VERSION 5.7 ;
  NOWIREEXTENSIONATPIN ON ;
  DIVIDERCHAR "/" ;
  BUSBITCHARS "[]" ;
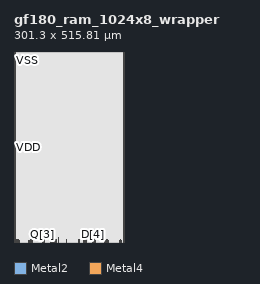
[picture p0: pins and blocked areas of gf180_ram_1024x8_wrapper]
MACRO gf180_ram_1024x8_wrapper
  CLASS BLOCK ;
  FOREIGN gf180_ram_1024x8_wrapper ;
  ORIGIN 0.000 0.000 ;
  SIZE 301.300 BY 515.810 ;
  PIN A[0]
    DIRECTION INPUT ;
    USE SIGNAL ;
    ANTENNADIFFAREA 0.928400 ;
    PORT
      LAYER Metal2 ;
        RECT 119.850 0.000 120.630 12.275 ;
    END
  END A[0]
  PIN A[1]
    DIRECTION INPUT ;
    USE SIGNAL ;
    ANTENNADIFFAREA 0.928400 ;
    PORT
      LAYER Metal2 ;
        RECT 113.930 0.000 114.720 6.000 ;
    END
  END A[1]
  PIN A[2]
    DIRECTION INPUT ;
    USE SIGNAL ;
    ANTENNADIFFAREA 0.928400 ;
    PORT
      LAYER Metal2 ;
        RECT 108.005 0.000 108.795 6.000 ;
    END
  END A[2]
  PIN A[3]
    DIRECTION INPUT ;
    USE SIGNAL ;
    ANTENNADIFFAREA 0.928400 ;
    PORT
      LAYER Metal2 ;
        RECT 196.925 0.000 197.715 6.000 ;
    END
  END A[3]
  PIN A[4]
    DIRECTION INPUT ;
    USE SIGNAL ;
    ANTENNADIFFAREA 0.928400 ;
    PORT
      LAYER Metal2 ;
        RECT 193.070 0.000 193.860 6.000 ;
    END
  END A[4]
  PIN A[5]
    DIRECTION INPUT ;
    USE SIGNAL ;
    ANTENNADIFFAREA 0.928400 ;
    PORT
      LAYER Metal2 ;
        RECT 190.455 0.000 191.245 6.000 ;
    END
  END A[5]
  PIN A[6]
    DIRECTION INPUT ;
    USE SIGNAL ;
    ANTENNADIFFAREA 0.928400 ;
    PORT
      LAYER Metal2 ;
        RECT 188.200 0.000 188.990 6.000 ;
    END
  END A[6]
  PIN A[7]
    DIRECTION INPUT ;
    USE SIGNAL ;
    ANTENNADIFFAREA 0.928400 ;
    PORT
      LAYER Metal2 ;
        RECT 103.965 0.000 104.755 6.000 ;
    END
  END A[7]
  PIN A[8]
    DIRECTION INPUT ;
    USE SIGNAL ;
    ANTENNADIFFAREA 0.928400 ;
    PORT
      LAYER Metal2 ;
        RECT 101.520 0.000 102.310 6.000 ;
    END
  END A[8]
  PIN A[9]
    DIRECTION INPUT ;
    USE SIGNAL ;
    ANTENNADIFFAREA 0.928400 ;
    PORT
      LAYER Metal2 ;
        RECT 99.650 0.000 100.440 6.000 ;
    END
  END A[9]
  PIN CEN
    DIRECTION INPUT ;
    USE SIGNAL ;
    ANTENNADIFFAREA 1.418650 ;
    PORT
      LAYER Metal2 ;
        RECT 176.195 0.000 176.985 6.000 ;
    END
  END CEN
  PIN CLK
    DIRECTION INPUT ;
    USE SIGNAL ;
    ANTENNAGATEAREA 9.738400 ;
    PORT
      LAYER Metal2 ;
        RECT 97.775 0.000 98.565 6.000 ;
    END
  END CLK
  PIN D[0]
    DIRECTION INPUT ;
    USE SIGNAL ;
    ANTENNAGATEAREA 0.249200 ;
    ANTENNADIFFAREA 0.490250 ;
    PORT
      LAYER Metal2 ;
        RECT 6.520 0.000 7.310 6.000 ;
    END
  END D[0]
  PIN D[1]
    DIRECTION INPUT ;
    USE SIGNAL ;
    ANTENNAGATEAREA 0.249200 ;
    ANTENNADIFFAREA 0.490250 ;
    PORT
      LAYER Metal2 ;
        RECT 42.720 0.000 43.510 4.170 ;
    END
  END D[1]
  PIN D[2]
    DIRECTION INPUT ;
    USE SIGNAL ;
    ANTENNAGATEAREA 0.249200 ;
    ANTENNADIFFAREA 0.490250 ;
    PORT
      LAYER Metal2 ;
        RECT 47.085 0.000 47.875 4.160 ;
    END
  END D[2]
  PIN D[3]
    DIRECTION INPUT ;
    USE SIGNAL ;
    ANTENNAGATEAREA 0.249200 ;
    ANTENNADIFFAREA 0.490250 ;
    PORT
      LAYER Metal2 ;
        RECT 83.280 0.000 84.070 4.850 ;
    END
  END D[3]
  PIN D[4]
    DIRECTION INPUT ;
    USE SIGNAL ;
    ANTENNAGATEAREA 0.249200 ;
    ANTENNADIFFAREA 0.490250 ;
    PORT
      LAYER Metal2 ;
        RECT 214.060 0.000 214.850 3.990 ;
    END
  END D[4]
  PIN D[5]
    DIRECTION INPUT ;
    USE SIGNAL ;
    ANTENNAGATEAREA 0.249200 ;
    ANTENNADIFFAREA 0.490250 ;
    PORT
      LAYER Metal2 ;
        RECT 249.235 0.000 250.025 4.250 ;
    END
  END D[5]
  PIN D[6]
    DIRECTION INPUT ;
    USE SIGNAL ;
    ANTENNAGATEAREA 0.249200 ;
    ANTENNADIFFAREA 0.490250 ;
    PORT
      LAYER Metal2 ;
        RECT 254.605 0.000 255.385 4.250 ;
    END
  END D[6]
  PIN D[7]
    DIRECTION INPUT ;
    USE SIGNAL ;
    ANTENNAGATEAREA 0.249200 ;
    ANTENNADIFFAREA 0.490250 ;
    PORT
      LAYER Metal2 ;
        RECT 290.800 0.000 291.590 4.875 ;
    END
  END D[7]
  PIN GWEN
    DIRECTION INPUT ;
    USE SIGNAL ;
    ANTENNAGATEAREA 3.141600 ;
    ANTENNADIFFAREA 0.490250 ;
    PORT
      LAYER Metal2 ;
        RECT 142.055 0.000 142.845 6.000 ;
    END
  END GWEN
  PIN Q[0]
    DIRECTION OUTPUT ;
    USE SIGNAL ;
    ANTENNADIFFAREA 5.315450 ;
    PORT
      LAYER Metal2 ;
        RECT 13.830 0.000 14.610 4.250 ;
    END
  END Q[0]
  PIN Q[1]
    DIRECTION OUTPUT ;
    USE SIGNAL ;
    ANTENNADIFFAREA 5.315450 ;
    PORT
      LAYER Metal2 ;
        RECT 40.365 0.000 41.145 4.200 ;
    END
  END Q[1]
  PIN Q[2]
    DIRECTION OUTPUT ;
    USE SIGNAL ;
    ANTENNADIFFAREA 5.315450 ;
    PORT
      LAYER Metal2 ;
        RECT 49.440 0.000 50.230 4.160 ;
    END
  END Q[2]
  PIN Q[3]
    DIRECTION OUTPUT ;
    USE SIGNAL ;
    ANTENNADIFFAREA 5.315450 ;
    PORT
      LAYER Metal2 ;
        RECT 77.975 0.000 78.765 4.130 ;
    END
  END Q[3]
  PIN Q[4]
    DIRECTION OUTPUT ;
    USE SIGNAL ;
    ANTENNADIFFAREA 5.315450 ;
    PORT
      LAYER Metal2 ;
        RECT 219.350 0.000 220.140 4.380 ;
    END
  END Q[4]
  PIN Q[5]
    DIRECTION OUTPUT ;
    USE SIGNAL ;
    ANTENNADIFFAREA 5.315450 ;
    PORT
      LAYER Metal2 ;
        RECT 246.880 0.000 247.670 4.250 ;
    END
  END Q[5]
  PIN Q[6]
    DIRECTION OUTPUT ;
    USE SIGNAL ;
    ANTENNADIFFAREA 5.315450 ;
    PORT
      LAYER Metal2 ;
        RECT 256.960 0.000 257.740 4.250 ;
    END
  END Q[6]
  PIN Q[7]
    DIRECTION OUTPUT ;
    USE SIGNAL ;
    ANTENNADIFFAREA 5.315450 ;
    PORT
      LAYER Metal2 ;
        RECT 285.490 0.000 286.280 4.250 ;
    END
  END Q[7]
  PIN VDD
    DIRECTION INOUT ;
    USE POWER ;
    PORT
      LAYER Metal4 ;
        RECT 0.000 0.000 2.000 513.520 ;
    END
    PORT
      LAYER Metal4 ;
        RECT 296.300 0.000 298.300 513.520 ;
    END
  END VDD
  PIN VSS
    DIRECTION INOUT ;
    USE GROUND ;
    PORT
      LAYER Metal4 ;
        RECT 3.000 0.000 5.000 513.520 ;
    END
    PORT
      LAYER Metal4 ;
        RECT 299.300 0.000 301.300 513.520 ;
    END
  END VSS
  PIN WEN[0]
    DIRECTION INPUT ;
    USE SIGNAL ;
    ANTENNAGATEAREA 0.420000 ;
    ANTENNADIFFAREA 0.490250 ;
    PORT
      LAYER Metal2 ;
        RECT 10.085 0.000 10.875 5.980 ;
    END
  END WEN[0]
  PIN WEN[1]
    DIRECTION INPUT ;
    USE SIGNAL ;
    ANTENNAGATEAREA 0.420000 ;
    ANTENNADIFFAREA 0.490250 ;
    PORT
      LAYER Metal2 ;
        RECT 44.110 0.000 44.900 6.000 ;
    END
  END WEN[1]
  PIN WEN[2]
    DIRECTION INPUT ;
    USE SIGNAL ;
    ANTENNAGATEAREA 0.420000 ;
    ANTENNADIFFAREA 0.490250 ;
    PORT
      LAYER Metal2 ;
        RECT 45.685 0.000 46.475 5.650 ;
    END
  END WEN[2]
  PIN WEN[3]
    DIRECTION INPUT ;
    USE SIGNAL ;
    ANTENNAGATEAREA 0.420000 ;
    ANTENNADIFFAREA 0.490250 ;
    PORT
      LAYER Metal2 ;
        RECT 81.910 0.000 82.700 6.000 ;
    END
  END WEN[3]
  PIN WEN[4]
    DIRECTION INPUT ;
    USE SIGNAL ;
    ANTENNAGATEAREA 0.420000 ;
    ANTENNADIFFAREA 0.490250 ;
    PORT
      LAYER Metal2 ;
        RECT 216.400 0.000 217.190 5.960 ;
    END
  END WEN[4]
  PIN WEN[5]
    DIRECTION INPUT ;
    USE SIGNAL ;
    ANTENNAGATEAREA 0.420000 ;
    ANTENNADIFFAREA 0.490250 ;
    PORT
      LAYER Metal2 ;
        RECT 250.630 0.000 251.410 6.000 ;
    END
  END WEN[5]
  PIN WEN[6]
    DIRECTION INPUT ;
    USE SIGNAL ;
    ANTENNAGATEAREA 0.420000 ;
    ANTENNADIFFAREA 0.490250 ;
    PORT
      LAYER Metal2 ;
        RECT 253.205 0.000 253.985 6.000 ;
    END
  END WEN[6]
  PIN WEN[7]
    DIRECTION INPUT ;
    USE SIGNAL ;
    ANTENNAGATEAREA 0.420000 ;
    ANTENNADIFFAREA 0.490250 ;
    PORT
      LAYER Metal2 ;
        RECT 288.430 0.000 289.220 6.000 ;
    END
  END WEN[7]
  OBS
      LAYER Nwell ;
        RECT 6.305 5.770 295.010 510.690 ;
      LAYER Metal1 ;
        RECT 0.985 0.980 300.315 514.820 ;
      LAYER Metal2 ;
        RECT 0.985 12.575 300.800 514.820 ;
        RECT 0.985 6.300 119.550 12.575 ;
        RECT 0.985 0.965 6.220 6.300 ;
        RECT 7.610 6.280 43.810 6.300 ;
        RECT 7.610 0.965 9.785 6.280 ;
        RECT 11.175 4.550 43.810 6.280 ;
        RECT 11.175 0.965 13.530 4.550 ;
        RECT 14.910 4.500 43.810 4.550 ;
        RECT 14.910 0.965 40.065 4.500 ;
        RECT 41.445 4.470 43.810 4.500 ;
        RECT 45.200 5.950 81.610 6.300 ;
        RECT 41.445 0.965 42.420 4.470 ;
        RECT 45.200 0.965 45.385 5.950 ;
        RECT 46.775 4.460 81.610 5.950 ;
        RECT 83.000 5.150 97.475 6.300 ;
        RECT 46.775 0.965 46.785 4.460 ;
        RECT 48.175 0.965 49.140 4.460 ;
        RECT 50.530 4.430 81.610 4.460 ;
        RECT 50.530 0.965 77.675 4.430 ;
        RECT 79.065 0.965 81.610 4.430 ;
        RECT 84.370 0.965 97.475 5.150 ;
        RECT 98.865 0.965 99.350 6.300 ;
        RECT 100.740 0.965 101.220 6.300 ;
        RECT 102.610 0.965 103.665 6.300 ;
        RECT 105.055 0.965 107.705 6.300 ;
        RECT 109.095 0.965 113.630 6.300 ;
        RECT 115.020 0.965 119.550 6.300 ;
        RECT 120.930 6.300 300.800 12.575 ;
        RECT 120.930 0.965 141.755 6.300 ;
        RECT 143.145 0.965 175.895 6.300 ;
        RECT 177.285 0.965 187.900 6.300 ;
        RECT 189.290 0.965 190.155 6.300 ;
        RECT 191.545 0.965 192.770 6.300 ;
        RECT 194.160 0.965 196.625 6.300 ;
        RECT 198.015 6.260 250.330 6.300 ;
        RECT 198.015 4.290 216.100 6.260 ;
        RECT 198.015 0.965 213.760 4.290 ;
        RECT 215.150 0.965 216.100 4.290 ;
        RECT 217.490 4.680 250.330 6.260 ;
        RECT 217.490 0.965 219.050 4.680 ;
        RECT 220.440 4.550 250.330 4.680 ;
        RECT 220.440 0.965 246.580 4.550 ;
        RECT 247.970 0.965 248.935 4.550 ;
        RECT 250.325 0.965 250.330 4.550 ;
        RECT 251.710 0.965 252.905 6.300 ;
        RECT 254.285 4.550 288.130 6.300 ;
        RECT 254.285 0.965 254.305 4.550 ;
        RECT 255.685 0.965 256.660 4.550 ;
        RECT 258.040 0.965 285.190 4.550 ;
        RECT 286.580 0.965 288.130 4.550 ;
        RECT 289.520 5.175 300.800 6.300 ;
        RECT 289.520 0.965 290.500 5.175 ;
        RECT 291.890 0.965 300.800 5.175 ;
      LAYER Metal3 ;
        RECT 0.000 0.000 301.300 515.810 ;
  END
END gf180_ram_1024x8_wrapper
END LIBRARY

